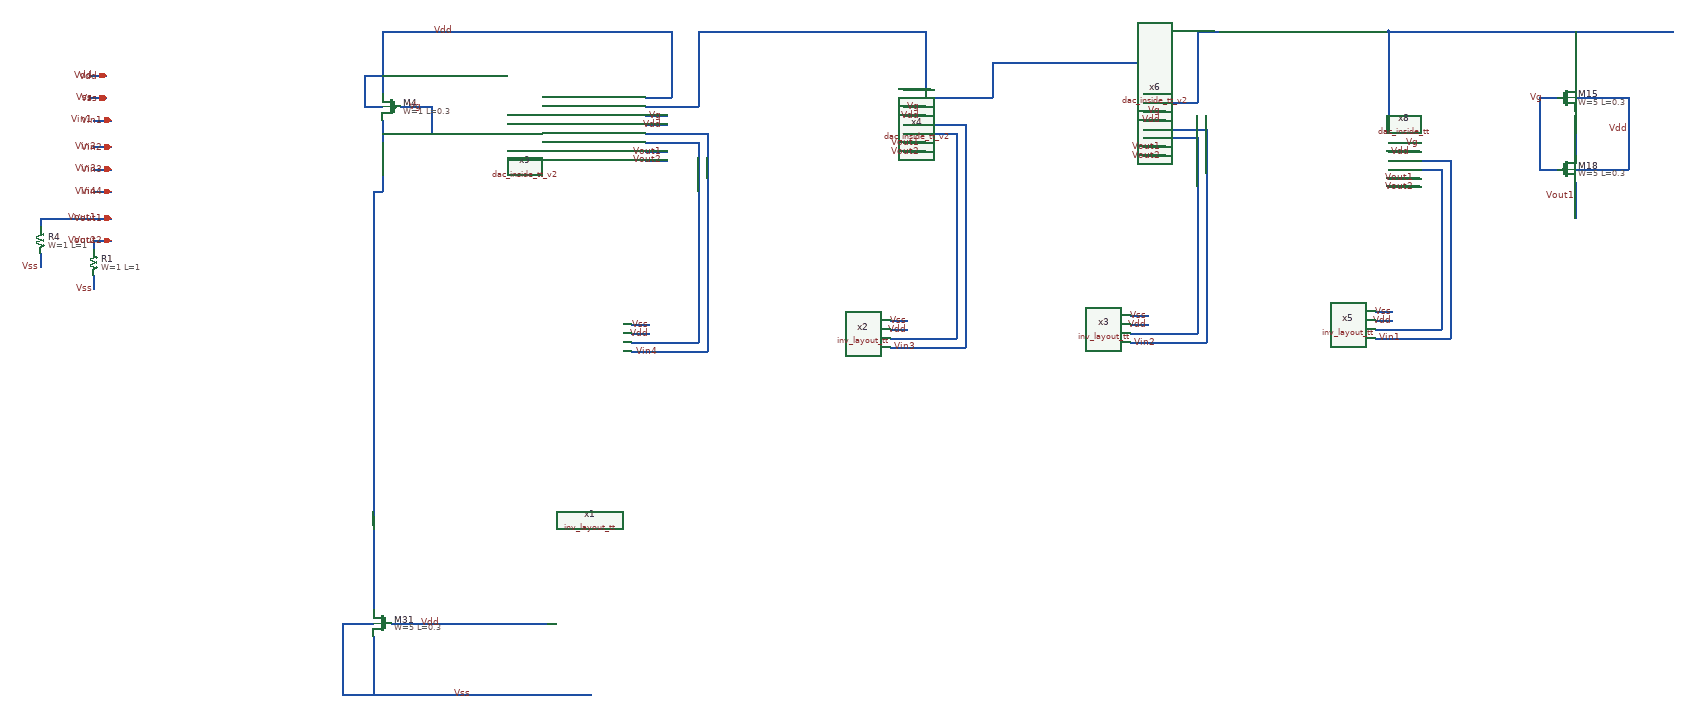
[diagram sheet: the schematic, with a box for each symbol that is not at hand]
v {xschem version=3.4.5 file_version=1.2
}
G {}
K {}
V {}
S {}
E {}
N -1600 -710 -1600 -570 {
lab=Vdd}
N -1600 -710 -1150 -710 {
lab=Vdd}
N -1600 -510 -1600 -450 {
lab=Vg}
N -1600 -480 -1490 -480 {
lab=Vg}
N -1490 -540 -1490 -480 {
lab=Vg}
N -1600 -460 -1600 -400 {
lab=Vg}
N 660 -710 660 -550 {
lab=#net1}
N 270 -710 660 -710 {
lab=#net1}
N 660 -710 780 -710 {
lab=#net1}
N 780 -710 840 -710 {
lab=#net1}
N -1640 -540 -1600 -540 {
lab=Vdd}
N -2260 -610 -2220 -610 {
lab=Vdd}
N -2260 -560 -2220 -560 {
lab=Vss}
N -2250 -510 -2210 -510 {
lab=Vin1}
N -2250 -290 -2210 -290 {
lab=Vout1}
N -2250 -240 -2210 -240 {
lab=Vout2}
N -1640 -610 -1640 -540 {
lab=Vdd}
N -1640 -610 -1600 -610 {
lab=Vdd}
N -2250 -450 -2210 -450 {
lab=Vin2}
N -2250 -400 -2210 -400 {
lab=Vin3}
N -2250 -350 -2210 -350 {
lab=Vin4}
N -890 -360 -890 -140 {
lab=#net2}
N -2370 -210 -2370 -180 {
lab=Vss}
N -2370 -280 -2370 -270 {
lab=Vout1}
N -2370 -290 -2370 -280 {
lab=Vout1}
N -2370 -290 -2240 -290 {
lab=Vout1}
N -2250 -160 -2250 -130 {
lab=Vss}
N -2250 -230 -2250 -220 {
lab=Vout2}
N -2250 -240 -2250 -230 {
lab=Vout2}
N -890 -140 -890 -110 {
lab=#net2}
N -1620 650 -1620 680 {
lab=Vss}
N -1580 620 -1550 620 {
lab=Vdd}
N -1620 680 -1620 780 {
lab=Vss}
N -1580 780 -1130 780 {
lab=Vss}
N -1690 620 -1620 620 {
lab=Vss}
N -1690 620 -1690 780 {
lab=Vss}
N -1690 780 -1570 780 {
lab=Vss}
N -1550 620 -1230 620 {
lab=Vdd}
N -1620 -350 -1620 400 {
lab=Vg}
N -1620 -350 -1600 -350 {
lab=Vg}
N -1600 -400 -1600 -350 {
lab=Vg}
N -1620 380 -1620 590 {
lab=Vg}
N -1040 -50 -1000 -50 {
lab=Vss}
N -1040 -30 -1000 -30 {
lab=Vdd}
N -1040 -10 -1000 -10 {
lab=#net2}
N -1040 10 -1000 10 {
lab=Vin4}
N -1000 -10 -890 -10 {
lab=#net2}
N -890 -110 -890 -10 {
lab=#net2}
N 840 -710 1300 -710 {
lab=#net1}
N 1080 -710 1080 -590 {
lab=#net1}
N 1000 -560 1040 -560 {
lab=Vg}
N 1080 -530 1080 -470 {
lab=#net3}
N 1080 -470 1080 -430 {
lab=#net3}
N 1080 -560 1200 -560 {
lab=Vdd}
N 1200 -560 1200 -400 {
lab=Vdd}
N 1080 -400 1200 -400 {
lab=Vdd}
N 1000 -400 1040 -400 {
lab=Vg}
N 1000 -560 1000 -400 {
lab=Vg}
N 1080 -370 1080 -290 {
lab=Vout1}
N -870 -390 -870 10 {
lab=Vin4}
N -1000 10 -870 10 {
lab=Vin4}
N -310 -370 -310 -150 {
lab=#net4}
N -310 -150 -310 -120 {
lab=#net4}
N -460 -60 -420 -60 {
lab=Vss}
N -460 -40 -420 -40 {
lab=Vdd}
N -460 -20 -420 -20 {
lab=#net4}
N -460 0 -420 0 {
lab=Vin3}
N -420 -20 -310 -20 {
lab=#net4}
N -310 -120 -310 -20 {
lab=#net4}
N -290 -400 -290 0 {
lab=Vin3}
N -420 0 -290 0 {
lab=Vin3}
N 230 -380 230 -160 {
lab=#net5}
N 230 -160 230 -130 {
lab=#net5}
N 80 -70 120 -70 {
lab=Vss}
N 80 -50 120 -50 {
lab=Vdd}
N 80 -30 120 -30 {
lab=#net5}
N 80 -10 120 -10 {
lab=Vin2}
N 120 -30 230 -30 {
lab=#net5}
N 230 -130 230 -30 {
lab=#net5}
N 250 -410 250 -10 {
lab=Vin2}
N 120 -10 250 -10 {
lab=Vin2}
N 780 -390 780 -170 {
lab=#net6}
N 780 -170 780 -140 {
lab=#net6}
N 630 -80 670 -80 {
lab=Vss}
N 630 -60 670 -60 {
lab=Vdd}
N 630 -40 670 -40 {
lab=#net6}
N 630 -20 670 -20 {
lab=Vin1}
N 670 -40 780 -40 {
lab=#net6}
N 780 -140 780 -40 {
lab=#net6}
N 780 -400 780 -390 {
lab=#net6}
N 660 -400 780 -400 {
lab=#net6}
N 660 -420 800 -420 {
lab=Vin1}
N 800 -420 800 -20 {
lab=Vin1}
N 670 -20 800 -20 {
lab=Vin1}
N 660 -440 730 -440 {
lab=Vdd}
N 660 -380 730 -380 {
lab=Vout1}
N 660 -360 730 -360 {
lab=Vout2}
N 660 -460 730 -460 {
lab=Vg}
N 660 -520 660 -480 {
lab=#net1}
N 660 -550 660 -540 {
lab=#net1}
N 660 -540 660 -510 {
lab=#net1}
N -1010 -520 -960 -520 {
lab=Vg}
N -1010 -500 -960 -500 {
lab=Vdd}
N -1010 -440 -960 -440 {
lab=Vout1}
N -1010 -420 -960 -420 {
lab=Vout2}
N -1560 -540 -1490 -540 {
lab=Vg}
N -1010 -560 -950 -560 {
lab=Vdd}
N -1010 -540 -940 -540 {
lab=#net7}
N -1010 -460 -900 -460 {
lab=#net2}
N -900 -460 -890 -460 {
lab=#net2}
N -890 -460 -890 -350 {
lab=#net2}
N -870 -480 -870 -390 {
lab=Vin4}
N -870 -390 -870 -380 {
lab=Vin4}
N -1010 -480 -870 -480 {
lab=Vin4}
N -940 -540 -890 -540 {
lab=#net7}
N -890 -710 -890 -540 {
lab=#net7}
N -890 -710 -380 -710 {
lab=#net7}
N -1150 -710 -960 -710 {
lab=Vdd}
N -960 -710 -950 -710 {
lab=Vdd}
N -950 -710 -950 -560 {
lab=Vdd}
N -430 -540 -380 -540 {
lab=Vg}
N -430 -520 -380 -520 {
lab=Vdd}
N -430 -460 -380 -460 {
lab=Vout1}
N -430 -440 -380 -440 {
lab=Vout2}
N -430 -580 -370 -580 {
lab=#net7}
N -430 -560 -360 -560 {
lab=#net8}
N -430 -480 -320 -480 {
lab=#net4}
N -320 -480 -310 -480 {
lab=#net4}
N -310 -480 -310 -370 {
lab=#net4}
N -290 -500 -290 -410 {
lab=Vin3}
N -290 -410 -290 -400 {
lab=Vin3}
N -430 -500 -290 -500 {
lab=Vin3}
N -360 -560 -310 -560 {
lab=#net8}
N -380 -710 -380 -580 {
lab=#net7}
N 110 -530 160 -530 {
lab=Vg}
N 110 -510 160 -510 {
lab=Vdd}
N 110 -450 160 -450 {
lab=Vout1}
N 110 -430 160 -430 {
lab=Vout2}
N 110 -570 170 -570 {
lab=#net8}
N 110 -550 180 -550 {
lab=#net1}
N 110 -470 220 -470 {
lab=#net5}
N 220 -470 230 -470 {
lab=#net5}
N 230 -470 230 -360 {
lab=#net5}
N 250 -490 250 -400 {
lab=Vin2}
N 250 -400 250 -390 {
lab=Vin2}
N 110 -490 250 -490 {
lab=Vin2}
N 180 -550 230 -550 {
lab=#net1}
N 230 -710 230 -550 {
lab=#net1}
N 230 -710 280 -710 {
lab=#net1}
N -310 -560 -230 -560 {
lab=#net8}
N -230 -640 -230 -560 {
lab=#net8}
N -230 -640 170 -640 {
lab=#net8}
N 170 -640 170 -570 {
lab=#net8}
C {sky130_fd_pr/pfet_01v8.sym} -1580 -540 0 1 {name=M4
L=0.3
W=1
nf=3 mult=10
model=pfet_01v8
spiceprefix=X
}
C {devices/iopin.sym} -2220 -610 0 0 {name=p1 lab=Vdd




}
C {devices/iopin.sym} -2220 -560 0 0 {name=p2 lab=Vss




}
C {devices/lab_wire.sym} -2250 -560 0 0 {name=p9 sig_type=std_logic lab=Vss}
C {devices/lab_wire.sym} -2250 -610 0 0 {name=p6 sig_type=std_logic lab=Vdd
}
C {devices/iopin.sym} -2210 -510 0 0 {name=p7 lab=Vin1





}
C {devices/lab_wire.sym} -2250 -510 0 0 {name=p8 sig_type=std_logic lab=Vin1

}
C {devices/iopin.sym} -2210 -290 0 0 {name=p10 lab=Vout1



}
C {devices/lab_wire.sym} -2240 -290 0 0 {name=p11 sig_type=std_logic lab=Vout1
}
C {devices/iopin.sym} -2210 -240 0 0 {name=p12 lab=Vout2




}
C {devices/lab_wire.sym} -2240 -240 0 0 {name=p13 sig_type=std_logic lab=Vout2
}
C {devices/lab_wire.sym} -1440 -710 0 0 {name=p16 sig_type=std_logic lab=Vdd
}
C {devices/iopin.sym} -2210 -450 0 0 {name=p40 lab=Vin2






}
C {devices/lab_wire.sym} -2240 -450 0 0 {name=p41 sig_type=std_logic lab=Vin2



}
C {devices/iopin.sym} -2210 -400 0 0 {name=p42 lab=Vin3





}
C {devices/lab_wire.sym} -2240 -400 0 0 {name=p43 sig_type=std_logic lab=Vin3

}
C {devices/iopin.sym} -2210 -350 0 0 {name=p44 lab=Vin4





}
C {devices/lab_wire.sym} -2240 -350 0 0 {name=p45 sig_type=std_logic lab=Vin4

}
C {devices/lab_pin.sym} -2370 -180 0 0 {name=p3 sig_type=std_logic lab=Vss
}
C {devices/lab_pin.sym} -2250 -130 0 0 {name=p5 sig_type=std_logic lab=Vss
}
C {sky130_fd_pr/res_generic_po.sym} -2370 -240 0 0 {name=R4
W=1
L=1
model=res_generic_po
spiceprefix=X
 mult=0.01}
C {sky130_fd_pr/res_generic_po.sym} -2250 -190 0 0 {name=R1
W=1
L=1
model=res_generic_po
spiceprefix=X
 mult=0.01}
C {sky130_fd_pr/nfet_01v8.sym} -1600 620 0 1 {name=M31
L=0.3
W=5
nf=3 mult=2
model=nfet_01v8
spiceprefix=X
}
C {devices/lab_wire.sym} -1400 780 0 0 {name=p74 sig_type=std_logic lab=Vss}
C {devices/lab_wire.sym} -1470 620 0 0 {name=p4 sig_type=std_logic lab=Vdd
}
C {devices/lab_wire.sym} -1000 -50 0 0 {name=p69 sig_type=std_logic lab=Vss
}
C {devices/lab_wire.sym} -1000 -30 0 0 {name=p70 sig_type=std_logic lab=Vdd
}
C {devices/lab_wire.sym} 1010 -560 0 0 {name=p25 sig_type=std_logic lab=Vg

}
C {devices/lab_wire.sym} 1200 -490 0 0 {name=p34 sig_type=std_logic lab=Vdd
}
C {devices/lab_wire.sym} 1080 -340 0 0 {name=p35 sig_type=std_logic lab=Vout1
}
C {/home/eserlis/inv_layout_tt.sym} -1190 -20 0 0 {name=x1}
C {sky130_fd_pr/pfet_01v8.sym} 1060 -560 0 0 {name=M15
L=0.3
W=5
nf=2 mult=1
model=pfet_01v8
spiceprefix=X
}
C {sky130_fd_pr/pfet_01v8.sym} 1060 -400 0 0 {name=M18
L=0.3
W=5
nf=2 mult=1
model=pfet_01v8
spiceprefix=X
}
C {devices/lab_wire.sym} -420 -60 0 0 {name=p15 sig_type=std_logic lab=Vss
}
C {devices/lab_wire.sym} -420 -40 0 0 {name=p21 sig_type=std_logic lab=Vdd
}
C {/home/eserlis/inv_layout_tt.sym} -610 -30 0 0 {name=x2}
C {devices/lab_wire.sym} -980 10 0 0 {name=p47 sig_type=std_logic lab=Vin4

}
C {devices/lab_wire.sym} -400 0 0 0 {name=p50 sig_type=std_logic lab=Vin3

}
C {devices/lab_wire.sym} 120 -70 0 0 {name=p18 sig_type=std_logic lab=Vss
}
C {devices/lab_wire.sym} 120 -50 0 0 {name=p23 sig_type=std_logic lab=Vdd
}
C {/home/eserlis/inv_layout_tt.sym} -70 -40 0 0 {name=x3}
C {devices/lab_wire.sym} 140 -10 0 0 {name=p51 sig_type=std_logic lab=Vin2

}
C {devices/lab_wire.sym} 670 -80 0 0 {name=p19 sig_type=std_logic lab=Vss
}
C {devices/lab_wire.sym} 670 -60 0 0 {name=p24 sig_type=std_logic lab=Vdd
}
C {/home/eserlis/inv_layout_tt.sym} 480 -50 0 0 {name=x5}
C {/home/eserlis/dac_inside_tt.sym} 510 -420 0 0 {name=x8}
C {devices/lab_wire.sym} 720 -380 0 0 {name=p32 sig_type=std_logic lab=Vout1
}
C {devices/lab_wire.sym} 720 -360 0 0 {name=p33 sig_type=std_logic lab=Vout2
}
C {devices/lab_wire.sym} 710 -440 0 0 {name=p38 sig_type=std_logic lab=Vdd
}
C {devices/lab_wire.sym} 730 -460 0 0 {name=p49 sig_type=std_logic lab=Vg

}
C {devices/lab_wire.sym} 690 -20 0 0 {name=p52 sig_type=std_logic lab=Vin1

}
C {/home/eserlis/dac_inside_tt_v2.sym} -1160 -490 0 0 {name=x9}
C {devices/lab_wire.sym} -970 -440 0 0 {name=p53 sig_type=std_logic lab=Vout1
}
C {devices/lab_wire.sym} -970 -420 0 0 {name=p54 sig_type=std_logic lab=Vout2
}
C {devices/lab_wire.sym} -970 -520 0 0 {name=p55 sig_type=std_logic lab=Vg

}
C {devices/lab_wire.sym} -970 -500 0 0 {name=p56 sig_type=std_logic lab=Vdd
}
C {devices/lab_wire.sym} -1510 -540 0 0 {name=p39 sig_type=std_logic lab=Vg
}
C {/home/eserlis/dac_inside_tt_v2.sym} -580 -510 0 0 {name=x4}
C {devices/lab_wire.sym} -390 -460 0 0 {name=p14 sig_type=std_logic lab=Vout1
}
C {devices/lab_wire.sym} -390 -440 0 0 {name=p17 sig_type=std_logic lab=Vout2
}
C {devices/lab_wire.sym} -390 -540 0 0 {name=p20 sig_type=std_logic lab=Vg

}
C {devices/lab_wire.sym} -390 -520 0 0 {name=p22 sig_type=std_logic lab=Vdd
}
C {/home/eserlis/dac_inside_tt_v2.sym} -40 -500 0 0 {name=x6}
C {devices/lab_wire.sym} 150 -450 0 0 {name=p26 sig_type=std_logic lab=Vout1
}
C {devices/lab_wire.sym} 150 -430 0 0 {name=p27 sig_type=std_logic lab=Vout2
}
C {devices/lab_wire.sym} 150 -530 0 0 {name=p28 sig_type=std_logic lab=Vg

}
C {devices/lab_wire.sym} 150 -510 0 0 {name=p29 sig_type=std_logic lab=Vdd
}
